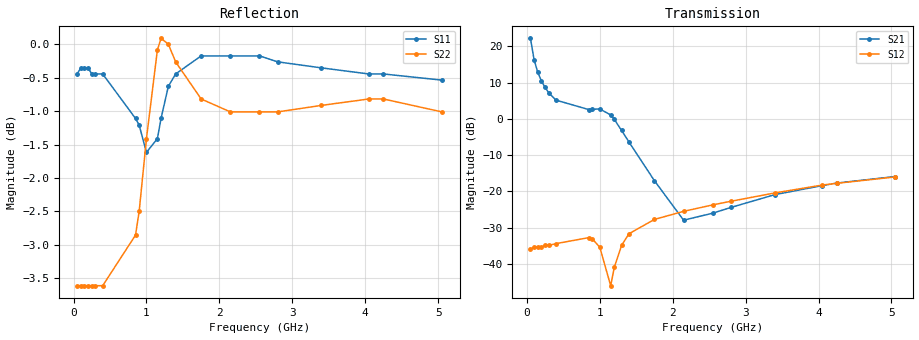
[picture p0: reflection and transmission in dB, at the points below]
!AT-36408
!S-PARAMETERS at Vce=4.8 V  Ic=100 mA.  LAST UPDATED 08-05-96
# ghz s ma r 50
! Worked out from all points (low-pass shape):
!   101 points, 50 MHz to 5.05 GHz, reference 50 ohm
!   highest |S21| = 22.18 dB at 50 MHz (marker M1); lowest = -28.0 dB at 2.15 GHz (marker M2)
!   |S21| within 3 dB of the highest: start of sweep to 75.37 MHz
!   lowest |S11| = -1.6 dB at 1 GHz (marker M3), VSWR 10.76, Z = 4.68 + j4.34 ohm
!   |S11| at or under -10 dB: nowhere
!   |S22| runs from -3.6 to 0.1 dB; largest |S21 - S12| = 13
!   S11 on the Smith chart (normalised r, x): 50 MHz: 0.03, -0.06; 850 MHz: 0.06, +0.10; 2.8 GHz: 0.02, +0.27; 4.05 GHz: 0.03, +0.44; 5.05 GHz: 0.04, +0.66
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0.05  0.95 -173.0  12.86 94.0  0.016 10.0  0.66 -165.0
0.1  0.96 -177.0  6.51 88.0  0.017 9.0  0.66 -171.0
0.15  0.96 -179.0  4.38 84.0  0.017 11.0  0.66 -174.0
0.2  0.96 179.0  3.33 80.0  0.017 12.0  0.66 -174.0
0.25  0.95 178.0  2.71 77.0  0.018 14.0  0.66 -174.0
0.3  0.95 177.0  2.29 74.0  0.018 16.0  0.66 -174.0
0.4  0.95 175.0  1.81 68.0  0.019 18.0  0.66 -173.0
0.85  0.88 169.0  1.34 27.0  0.023 6.0  0.72 -162.0
0.9  0.87 169.0  1.35 19.0  0.022 -1.0  0.75 -160.0
1  0.83 170.0  1.37 -2.0  0.017 -22.0  0.85 -158.0
1.15  0.85 174.0  1.13 -41.0  0.005 -139.0  0.99 -164.0
1.2  0.88 175.0  0.98 -54.0  0.009 164.0  1.01 -167.0
1.3  0.93 174.0  0.69 -75.0  0.018 127.0  1 -172.0
1.4  0.95 172.0  0.48 -90.0  0.026 112.0  0.97 -175.0
1.75  0.98 165.0  0.14 -125.0  0.041 90.0  0.91 -178.0
2.15  0.98 159.0  0.04 173.0  0.053 82.0  0.89 -178.0
2.55  0.98 154.0  0.05 106.0  0.065 78.0  0.89 -178.0
2.8  0.97 150.0  0.06 90.0  0.073 76.0  0.89 -178.0
3.4  0.96 142.0  0.09 74.0  0.095 71.0  0.9 -180.0
4.05  0.95 132.0  0.12 63.0  0.122 62.0  0.91 177.0
4.25  0.95 129.0  0.13 60.0  0.129 59.0  0.91 175.0
5.05  0.94 113.0  0.16 48.0  0.158 49.0  0.89 169.0
